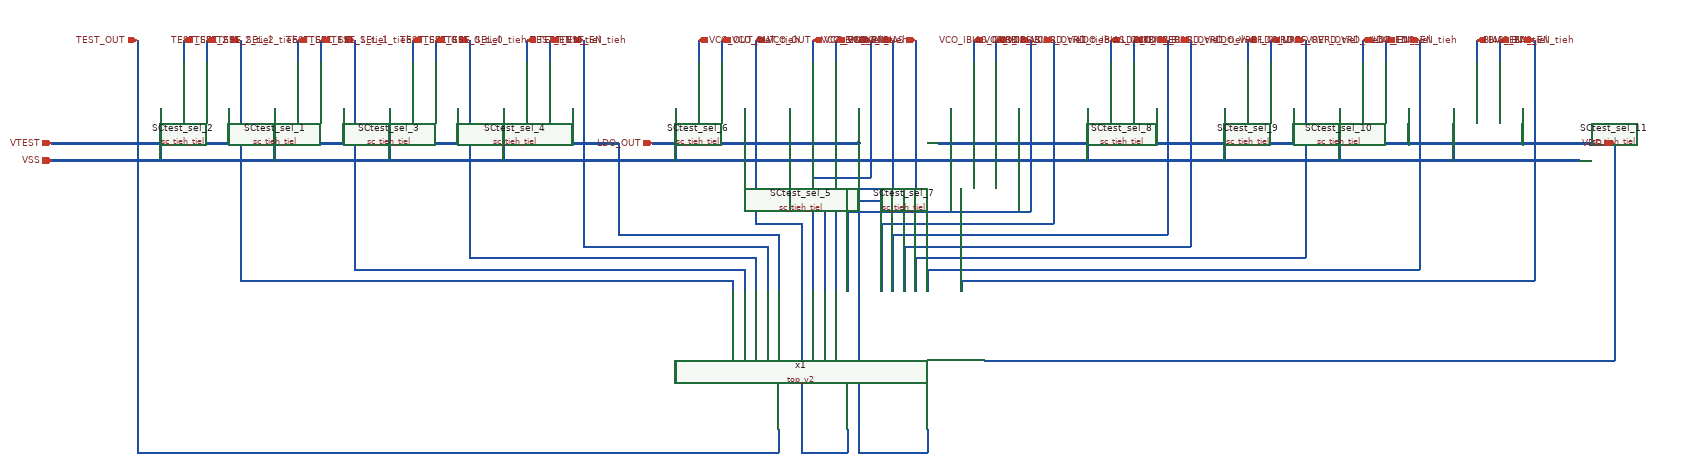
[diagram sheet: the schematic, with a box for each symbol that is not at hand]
v {xschem version=3.4.7 file_version=1.2}
G {}
K {}
V {}
S {}
E {}
N 1220 -880 1220 -860 {lab=TEST_SEL_2}
N 360 -880 1220 -880 {lab=TEST_SEL_2}
N 360 -1300 360 -880 {lab=TEST_SEL_2}
N 1240 -900 1240 -860 {lab=TEST_SEL_1}
N 560 -900 1240 -900 {lab=TEST_SEL_1}
N 560 -1300 560 -900 {lab=TEST_SEL_1}
N 1260 -920 1260 -860 {lab=TEST_SEL_0}
N 760 -920 1260 -920 {lab=TEST_SEL_0}
N 760 -1300 760 -920 {lab=TEST_SEL_0}
N 1120 -740 1120 -700 {lab=#net1}
N 1660 -740 2760 -740 {lab=VDD}
N 30 -1120 1020 -1120 {lab=VTEST
bus=true
color=blue}
N 30 -1090 2700 -1090 {lab=VSS
bus=true
color=blue}
N 260 -1300 260 -1260 {lab=TEST_SEL_2_tiel}
N 300 -1300 300 -1260 {lab=TEST_SEL_2_tieh}
N 460 -1300 460 -1260 {lab=TEST_SEL_1_tiel}
N 500 -1300 500 -1260 {lab=TEST_SEL_1_tieh}
N 660 -1300 660 -1260 {lab=TEST_SEL_0_tiel}
N 700 -1300 700 -1260 {lab=TEST_SEL_0_tieh}
N 1300 -620 1300 -580 {lab=TEST_OUT}
N 180 -580 1300 -580 {lab=TEST_OUT}
N 180 -1300 180 -580 {lab=TEST_OUT}
N 340 -1180 340 -1120 {lab=VTEST}
N 540 -1180 540 -1120 {lab=VTEST}
N 740 -1180 740 -1120 {lab=VTEST}
N 220 -1180 220 -1090 {lab=VSS}
N 420 -1180 420 -1090 {lab=VSS}
N 620 -1180 620 -1090 {lab=VSS}
N 960 -1300 960 -1060 {lab=TEST_EN}
N 860 -1300 860 -1260 {lab=TEST_EN_tiel}
N 900 -1300 900 -1260 {lab=TEST_EN_tieh}
N 940 -1180 940 -1120 {lab=VTEST}
N 820 -1180 820 -1090 {lab=VSS}
N 960 -1060 960 -940 {lab=TEST_EN}
N 1280 -940 1280 -860 {lab=TEST_EN}
N 960 -940 1280 -940 {lab=TEST_EN}
N 1300 -960 1300 -860 {lab=VTEST}
N 1020 -960 1300 -960 {lab=VTEST}
N 1020 -1120 1020 -960 {lab=VTEST}
N 1460 -1300 1460 -1060 {lab=VCO_EN}
N 1360 -1300 1360 -1260 {lab=VCO_EN_tiel}
N 1400 -1300 1400 -1260 {lab=VCO_EN_tieh}
N 1440 -1180 1440 -1120 {lab=LDO_OUT}
N 1320 -1180 1320 -1090 {lab=VSS}
N 1420 -620 1420 -580 {lab=VCO_OUT}
N 1340 -580 1420 -580 {lab=VCO_OUT}
N 1340 -980 1340 -580 {lab=VCO_OUT}
N 1260 -980 1340 -980 {lab=VCO_OUT}
N 1260 -1300 1260 -980 {lab=VCO_OUT}
N 1560 -620 1560 -580 {lab=LDO_OUT}
N 1440 -580 1560 -580 {lab=LDO_OUT}
N 1440 -1120 1440 -580 {lab=LDO_OUT}
N 1080 -1120 1440 -1120 {lab=LDO_OUT
bus=true}
N 1160 -1300 1160 -1260 {lab=VCO_OUT_tiel}
N 1200 -1300 1200 -1260 {lab=VCO_OUT_tieh}
N 1240 -1180 1240 -1120 {lab=LDO_OUT}
N 1120 -1180 1120 -1090 {lab=VSS}
N 1360 -1060 1360 -860 {lab=VCO_EN}
N 1360 -1060 1460 -1060 {lab=VCO_EN}
N 1380 -1040 1380 -860 {lab=VCO_IN}
N 1380 -1040 1500 -1040 {lab=VCO_IN}
N 1500 -1300 1500 -1040 {lab=VCO_IN}
N 1400 -1020 1400 -860 {lab=VCO_IBIAS}
N 1400 -1020 1540 -1020 {lab=VCO_IBIAS}
N 1540 -1300 1540 -1020 {lab=VCO_IBIAS}
N 1420 -1000 1420 -860 {lab=VCO_IBIAS_OVRD}
N 1420 -1000 1740 -1000 {lab=VCO_IBIAS_OVRD}
N 1480 -980 1480 -860 {lab=LCO_IBIAS}
N 1480 -980 1780 -980 {lab=LCO_IBIAS}
N 1500 -960 1500 -860 {lab=LDO_IBIAS_OVRD}
N 1500 -960 1980 -960 {lab=LDO_IBIAS_OVRD}
N 1520 -940 1520 -860 {lab=LCO_VREF}
N 1520 -940 2020 -940 {lab=LCO_VREF}
N 1540 -920 1540 -860 {lab=LDO_VREF_OVRD}
N 1540 -920 2220 -920 {lab=LDO_VREF_OVRD}
N 1560 -900 1560 -860 {lab=LDO_EN}
N 1560 -900 2420 -900 {lab=LDO_EN}
N 1620 -880 1620 -860 {lab=BIAS_EN}
N 1620 -880 2620 -880 {lab=BIAS_EN}
N 1640 -1300 1640 -1260 {lab=VCO_IBIAS_OVRD_tiel}
N 1680 -1300 1680 -1260 {lab=VCO_IBIAS_OVRD_tieh}
N 1720 -1180 1720 -1120 {lab=VDD}
N 1600 -1180 1600 -1090 {lab=VSS}
N 1740 -1300 1740 -1000 {lab=VCO_IBIAS_OVRD}
N 1580 -1120 2760 -1120 {lab=VDD
bus=true}
N 1780 -1300 1780 -980 {lab=LCO_IBIAS}
N 1880 -1300 1880 -1260 {lab=LDO_IBIAS_OVRD_tiel}
N 1920 -1300 1920 -1260 {lab=LDO_IBIAS_OVRD_tieh}
N 1960 -1180 1960 -1120 {lab=VDD}
N 1840 -1180 1840 -1090 {lab=VSS}
N 1980 -1300 1980 -960 {lab=LDO_IBIAS_OVRD}
N 2020 -1300 2020 -940 {lab=LCO_VREF}
N 2120 -1300 2120 -1260 {lab=LDO_VREF_OVRD_tiel}
N 2160 -1300 2160 -1260 {lab=LDO_VREF_OVRD_tieh}
N 2200 -1180 2200 -1120 {lab=VDD}
N 2080 -1180 2080 -1090 {lab=VSS}
N 2220 -1300 2220 -920 {lab=LDO_VREF_OVRD}
N 2320 -1300 2320 -1260 {lab=LDO_EN_tiel}
N 2360 -1300 2360 -1260 {lab=LDO_EN_tieh}
N 2400 -1180 2400 -1120 {lab=VDD}
N 2280 -1180 2280 -1090 {lab=VSS}
N 2520 -1300 2520 -1260 {lab=LDO_VREF_OVRD_tiel}
N 2560 -1300 2560 -1260 {lab=BIAS_EN_tieh}
N 2600 -1180 2600 -1120 {lab=VDD}
N 2480 -1180 2480 -1090 {lab=VSS}
N 2420 -1300 2420 -900 {lab=LDO_EN}
N 2620 -1300 2620 -880 {lab=BIAS_EN}
N 2760 -1120 2760 -740 {lab=VDD}
C {libs/core_top/top/top_v2.sym} 1120 -860 1 0 {name=x1}
C {gf180mcu_fd_sc_mcu9t5v0/xschem/symbols/sc_tieh_tiel.sym} 220 -1140 1 1 {name=SCtest_sel_2
spiceprefix=X
}
C {ipin.sym} 360 -1300 1 0 {name=p1 lab=TEST_SEL_2}
C {opin.sym} 260 -1300 3 0 {name=p2 lab=TEST_SEL_2_tiel}
C {opin.sym} 300 -1300 3 0 {name=p3 lab=TEST_SEL_2_tieh}
C {iopin.sym} 30 -1120 2 0 {name=p4 lab=VTEST}
C {iopin.sym} 30 -1090 2 0 {name=p5 lab=VSS}
C {gf180mcu_fd_sc_mcu9t5v0/xschem/symbols/sc_tieh_tiel.sym} 420 -1140 1 1 {name=SCtest_sel_1
spiceprefix=X
}
C {ipin.sym} 560 -1300 1 0 {name=p6 lab=TEST_SEL_1}
C {opin.sym} 460 -1300 3 0 {name=p7 lab=TEST_SEL_1_tiel}
C {opin.sym} 500 -1300 3 0 {name=p8 lab=TEST_SEL_1_tieh}
C {gf180mcu_fd_sc_mcu9t5v0/xschem/symbols/sc_tieh_tiel.sym} 620 -1140 1 1 {name=SCtest_sel_3
spiceprefix=X
}
C {ipin.sym} 760 -1300 1 0 {name=p9 lab=TEST_SEL_0}
C {opin.sym} 660 -1300 3 0 {name=p10 lab=TEST_SEL_0_tiel}
C {opin.sym} 700 -1300 3 0 {name=p11 lab=TEST_SEL_0_tieh}
C {gf180mcu_fd_sc_mcu9t5v0/xschem/symbols/sc_tieh_tiel.sym} 820 -1140 1 1 {name=SCtest_sel_4
spiceprefix=X
}
C {ipin.sym} 960 -1300 1 0 {name=p13 lab=TEST_EN}
C {opin.sym} 860 -1300 3 0 {name=p14 lab=TEST_EN_tiel}
C {opin.sym} 900 -1300 3 0 {name=p15 lab=TEST_EN_tieh}
C {gf180mcu_fd_sc_mcu9t5v0/xschem/symbols/sc_tieh_tiel.sym} 1320 -1140 1 1 {name=SCtest_sel_5
spiceprefix=X
}
C {ipin.sym} 1460 -1300 1 0 {name=p16 lab=VCO_EN}
C {opin.sym} 1360 -1300 3 0 {name=p17 lab=VCO_EN_tiel}
C {opin.sym} 1400 -1300 3 0 {name=p18 lab=VCO_EN_tieh}
C {iopin.sym} 1080 -1120 3 0 {name=p19 lab=LDO_OUT}
C {opin.sym} 1260 -1300 3 0 {name=p20 lab=VCO_OUT}
C {gf180mcu_fd_sc_mcu9t5v0/xschem/symbols/sc_tieh_tiel.sym} 1120 -1140 1 1 {name=SCtest_sel_6
spiceprefix=X
}
C {opin.sym} 1160 -1300 3 0 {name=p21 lab=VCO_OUT_tiel}
C {opin.sym} 1200 -1300 3 0 {name=p22 lab=VCO_OUT_tieh}
C {gf180mcu_fd_sc_mcu9t5v0/xschem/symbols/sc_tieh_tiel.sym} 1600 -1140 1 1 {name=SCtest_sel_7
spiceprefix=X
}
C {opin.sym} 1640 -1300 3 0 {name=p23 lab=VCO_IBIAS_OVRD_tiel}
C {opin.sym} 1680 -1300 3 0 {name=p24 lab=VCO_IBIAS_OVRD_tieh}
C {gf180mcu_fd_sc_mcu9t5v0/xschem/symbols/sc_tieh_tiel.sym} 1840 -1140 1 1 {name=SCtest_sel_8
spiceprefix=X
}
C {opin.sym} 2120 -1300 3 0 {name=p25 lab=LDO_VREF_OVRD_tiel}
C {opin.sym} 2160 -1300 3 0 {name=p26 lab=LDO_VREF_OVRD_tieh}
C {gf180mcu_fd_sc_mcu9t5v0/xschem/symbols/sc_tieh_tiel.sym} 2080 -1140 1 1 {name=SCtest_sel_9
spiceprefix=X
}
C {opin.sym} 1880 -1300 3 0 {name=p27 lab=LDO_IBIAS_OVRD_tiel}
C {opin.sym} 1920 -1300 3 0 {name=p28 lab=LDO_IBIAS_OVRD_tieh}
C {iopin.sym} 180 -1300 3 0 {name=p29 lab=TEST_OUT}
C {iopin.sym} 1500 -1300 3 0 {name=p12 lab=VCO_IN}
C {iopin.sym} 1540 -1300 3 0 {name=p30 lab=VCO_IBIAS}
C {iopin.sym} 1740 -1300 3 0 {name=p31 lab=VCO_IBIAS_OVRD}
C {iopin.sym} 2020 -1300 3 0 {name=p32 lab=LCO_VREF}
C {ipin.sym} 2220 -1300 1 0 {name=p33 lab=LDO_VREF_OVRD}
C {iopin.sym} 1780 -1300 3 0 {name=p34 lab=LCO_IBIAS}
C {ipin.sym} 1980 -1300 1 0 {name=p35 lab=LDO_IBIAS_OVRD}
C {opin.sym} 2320 -1300 3 0 {name=p36 lab=LDO_EN_tiel}
C {opin.sym} 2360 -1300 3 0 {name=p37 lab=LDO_EN_tieh}
C {gf180mcu_fd_sc_mcu9t5v0/xschem/symbols/sc_tieh_tiel.sym} 2280 -1140 1 1 {name=SCtest_sel_10
spiceprefix=X
}
C {ipin.sym} 2420 -1300 1 0 {name=p38 lab=LDO_EN}
C {opin.sym} 2520 -1300 3 0 {name=p39 lab=BIAS_EN_tiel}
C {opin.sym} 2560 -1300 3 0 {name=p40 lab=BIAS_EN_tieh}
C {gf180mcu_fd_sc_mcu9t5v0/xschem/symbols/sc_tieh_tiel.sym} 2480 -1140 1 1 {name=SCtest_sel_11
spiceprefix=X
}
C {ipin.sym} 2620 -1300 1 0 {name=p41 lab=BIAS_EN}
C {iopin.sym} 2760 -1120 0 0 {name=p42 lab=VDD}
